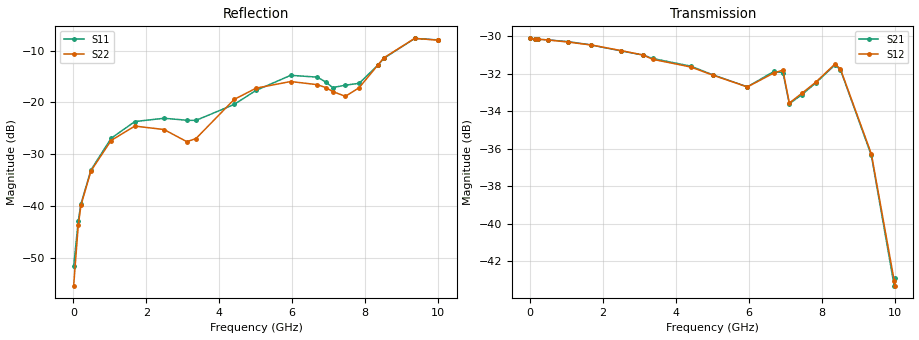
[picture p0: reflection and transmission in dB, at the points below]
! Device ID: PE43704
! Dir: z:\PE43704\PE43704_Char_1_20130516\PE43704\AMB\3p400V\29p25dB
! Serial: 14
! Insertion: A
! Impedance: 50 ohm
! Temp: Amb
! VDD: 3.400V
! Attenuation Step: 29.25dB
! IDD: 1.140195e-01mA
#  Hz  S  RI  R  50
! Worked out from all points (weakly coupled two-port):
!   401 points, 10 MHz to 10.01 GHz, reference 50 ohm
!   highest |S21| = -30.13 dB at 10 MHz (marker M1); lowest = -43.3 dB at 9.985 GHz (marker M2)
!   lowest |S11| = -51.7 dB at 10 MHz (marker M3), VSWR 1.01, Z = 50.3 + j0.0426 ohm
!   |S11| at or under -10 dB: start of sweep to 8.725 GHz
!   |S22| runs from -55.4 to -7.6 dB; largest |S21 - S12| = 0.00056
!   S11 on the Smith chart (normalised r, x): 10 MHz: 1.01, +0.00; 7.46 GHz: 0.78, +0.15; 8.51 GHz: 0.81, +0.46; 9.36 GHz: 0.54, +0.49; 10.01 GHz: 0.47, +0.28
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1e7  0.00256 0.000424  0.0312 -7.19e-05  0.0312 -9.85e-05  -0.00164 0.00042
1.35e8  0.00248 0.00666  0.031 -0.00106  0.031 -0.00105  -0.00172 0.00626
2.1e8  0.0013 0.0104  0.031 -0.00164  0.031 -0.00158  -0.00269 0.00979
4.85e8  -0.00583 0.0215  0.0307 -0.00355  0.0307 -0.00357  -0.00954 0.0196
1.035e9  -0.0333 0.0301  0.0297 -0.00735  0.0296 -0.00737  -0.0346 0.0252
1.685e9  -0.0632 0.0161  0.0277 -0.0114  0.0277 -0.0114  -0.0584 0.00827
2.485e9  -0.07 -0.00534  0.0244 -0.0155  0.0244 -0.0156  -0.0542 -0.00713
3.11e9  -0.067 -0.00522  0.0214 -0.0183  0.0214 -0.0183  -0.0416 0.00354
3.36e9  -0.0669 0.000589  0.02 -0.019  0.0199 -0.0189  -0.0429 0.0122
4.41e9  -0.0841 0.0453  0.0153 -0.0214  0.0152 -0.0213  -0.0902 0.0571
5.01e9  -0.1075 0.074  0.013 -0.0213  0.0129 -0.0213  -0.1227 0.0612
5.96e9  -0.1545 0.0972  0.00864 -0.0215  0.00861 -0.0215  -0.1484 0.057
6.685e9  -0.1542 0.0833  0.00694 -0.0245  0.00678 -0.0243  -0.138 0.0543
6.935e9  -0.137 0.0753  0.00307 -0.0251  0.00291 -0.0255  -0.1237 0.0621
7.11e9  -0.1231 0.0644  0.00187 -0.0208  0.00185 -0.0209  -0.1063 0.0699
7.46e9  -0.1125 0.094  0.00302 -0.0219  0.00296 -0.0221  -0.0772 0.0844
7.835e9  -0.0656 0.1379  0.00257 -0.0236  0.00262 -0.0237  -0.0608 0.1243
8.36e9  -0.0329 0.2284  -0.00509 -0.026  -0.00537 -0.0261  -0.0775 0.2182
8.51e9  -0.0361 0.2633  -0.00793 -0.0245  -0.00775 -0.0247  -0.0905 0.2533
9.36e9  -0.1779 0.3745  -0.011 -0.0105  -0.0111 -0.0106  -0.2424 0.3372
9.985e9  -0.3078 0.258  -0.00205 -0.00653  -0.00181 -0.00682  -0.3549 0.1828
1.001e10  -0.313 0.2499  -0.00171 -0.00697  -0.00128 -0.00672  -0.3589 0.1745
